VERSION 5.8 ;
BUSBITCHARS "[]" ;
DIVIDERCHAR "/" ;
UNITS
  DATABASE MICRONS 1000 ;
END UNITS
MANUFACTURINGGRID 0.005 ;

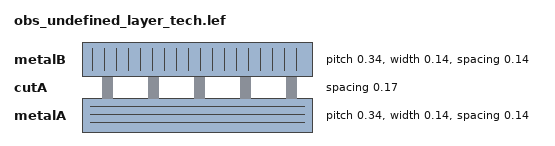
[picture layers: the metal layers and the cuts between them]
LAYER metalA
  TYPE ROUTING ;
  DIRECTION HORIZONTAL ;
  PITCH 0.34 ;
  WIDTH 0.14 ;
  SPACING 0.14 ;
END metalA

LAYER cutA
  TYPE CUT ;
  SPACING 0.17 ;
END cutA

LAYER metalB
  TYPE ROUTING ;
  DIRECTION VERTICAL ;
  PITCH 0.34 ;
  WIDTH 0.14 ;
  SPACING 0.14 ;
END metalB

SITE coreSite
  SYMMETRY Y ;
  CLASS CORE ;
  SIZE 0.46 BY 2.72 ;
END coreSite

END LIBRARY
